# OpenTallas memory compiler (tools/mem_compiler), ASAP7 abstract view
VERSION 5.7 ;
BUSBITCHARS "[]" ;
DIVIDERCHAR "/" ;
PROPERTYDEFINITIONS
  MACRO width INTEGER ;
  MACRO depth INTEGER ;
  MACRO banks INTEGER ;
END PROPERTYDEFINITIONS
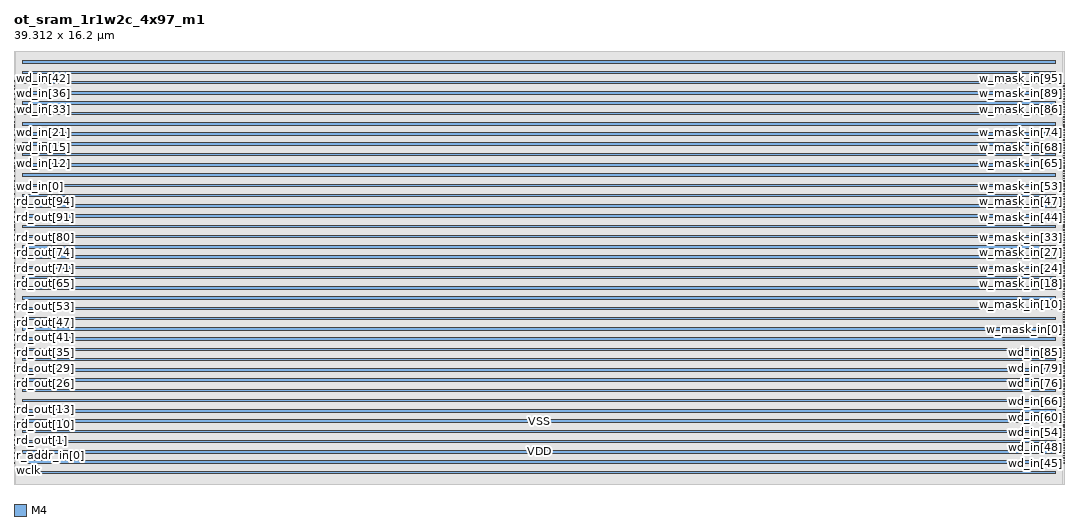
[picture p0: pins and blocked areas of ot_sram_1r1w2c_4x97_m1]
MACRO ot_sram_1r1w2c_4x97_m1
  PROPERTY width 97 ;
  PROPERTY depth 4 ;
  PROPERTY banks 1 ;
  FOREIGN ot_sram_1r1w2c_4x97_m1 0 0 ;
  SYMMETRY X Y R90 ;
  SIZE 39.312 BY 16.200 ;
  CLASS BLOCK ;
  PIN wclk
    DIRECTION INPUT ;
    USE CLOCK ;
    SHAPE ABUTMENT ;
    PORT
      LAYER M4 ;
      RECT 0.000 0.768 0.024 0.792 ;
    END
  END wclk
  PIN rclk
    DIRECTION INPUT ;
    USE CLOCK ;
    SHAPE ABUTMENT ;
    PORT
      LAYER M4 ;
      RECT 0.000 0.864 0.024 0.888 ;
    END
  END rclk
  PIN r_ce_in
    DIRECTION INPUT ;
    USE SIGNAL ;
    SHAPE ABUTMENT ;
    PORT
      LAYER M4 ;
      RECT 0.000 0.960 0.024 0.984 ;
    END
  END r_ce_in
  PIN r_addr_in[0]
    DIRECTION INPUT ;
    USE SIGNAL ;
    SHAPE ABUTMENT ;
    PORT
      LAYER M4 ;
      RECT 0.000 1.056 0.024 1.080 ;
    END
  END r_addr_in[0]
  PIN r_addr_in[1]
    DIRECTION INPUT ;
    USE SIGNAL ;
    SHAPE ABUTMENT ;
    PORT
      LAYER M4 ;
      RECT 0.000 1.152 0.024 1.176 ;
    END
  END r_addr_in[1]
  PIN rd_out[0]
    DIRECTION OUTPUT ;
    USE SIGNAL ;
    SHAPE ABUTMENT ;
    PORT
      LAYER M4 ;
      RECT 0.000 1.248 0.024 1.272 ;
    END
  END rd_out[0]
  PIN rd_out[1]
    DIRECTION OUTPUT ;
    USE SIGNAL ;
    SHAPE ABUTMENT ;
    PORT
      LAYER M4 ;
      RECT 0.000 1.344 0.024 1.368 ;
    END
  END rd_out[1]
  PIN rd_out[2]
    DIRECTION OUTPUT ;
    USE SIGNAL ;
    SHAPE ABUTMENT ;
    PORT
      LAYER M4 ;
      RECT 0.000 1.440 0.024 1.464 ;
    END
  END rd_out[2]
  PIN rd_out[3]
    DIRECTION OUTPUT ;
    USE SIGNAL ;
    SHAPE ABUTMENT ;
    PORT
      LAYER M4 ;
      RECT 0.000 1.536 0.024 1.560 ;
    END
  END rd_out[3]
  PIN rd_out[4]
    DIRECTION OUTPUT ;
    USE SIGNAL ;
    SHAPE ABUTMENT ;
    PORT
      LAYER M4 ;
      RECT 0.000 1.632 0.024 1.656 ;
    END
  END rd_out[4]
  PIN rd_out[5]
    DIRECTION OUTPUT ;
    USE SIGNAL ;
    SHAPE ABUTMENT ;
    PORT
      LAYER M4 ;
      RECT 0.000 1.728 0.024 1.752 ;
    END
  END rd_out[5]
  PIN rd_out[6]
    DIRECTION OUTPUT ;
    USE SIGNAL ;
    SHAPE ABUTMENT ;
    PORT
      LAYER M4 ;
      RECT 0.000 1.824 0.024 1.848 ;
    END
  END rd_out[6]
  PIN rd_out[7]
    DIRECTION OUTPUT ;
    USE SIGNAL ;
    SHAPE ABUTMENT ;
    PORT
      LAYER M4 ;
      RECT 0.000 1.920 0.024 1.944 ;
    END
  END rd_out[7]
  PIN rd_out[8]
    DIRECTION OUTPUT ;
    USE SIGNAL ;
    SHAPE ABUTMENT ;
    PORT
      LAYER M4 ;
      RECT 0.000 2.016 0.024 2.040 ;
    END
  END rd_out[8]
  PIN rd_out[9]
    DIRECTION OUTPUT ;
    USE SIGNAL ;
    SHAPE ABUTMENT ;
    PORT
      LAYER M4 ;
      RECT 0.000 2.112 0.024 2.136 ;
    END
  END rd_out[9]
  PIN rd_out[10]
    DIRECTION OUTPUT ;
    USE SIGNAL ;
    SHAPE ABUTMENT ;
    PORT
      LAYER M4 ;
      RECT 0.000 2.208 0.024 2.232 ;
    END
  END rd_out[10]
  PIN rd_out[11]
    DIRECTION OUTPUT ;
    USE SIGNAL ;
    SHAPE ABUTMENT ;
    PORT
      LAYER M4 ;
      RECT 0.000 2.304 0.024 2.328 ;
    END
  END rd_out[11]
  PIN rd_out[12]
    DIRECTION OUTPUT ;
    USE SIGNAL ;
    SHAPE ABUTMENT ;
    PORT
      LAYER M4 ;
      RECT 0.000 2.400 0.024 2.424 ;
    END
  END rd_out[12]
  PIN rd_out[13]
    DIRECTION OUTPUT ;
    USE SIGNAL ;
    SHAPE ABUTMENT ;
    PORT
      LAYER M4 ;
      RECT 0.000 2.496 0.024 2.520 ;
    END
  END rd_out[13]
  PIN rd_out[14]
    DIRECTION OUTPUT ;
    USE SIGNAL ;
    SHAPE ABUTMENT ;
    PORT
      LAYER M4 ;
      RECT 0.000 2.592 0.024 2.616 ;
    END
  END rd_out[14]
  PIN rd_out[15]
    DIRECTION OUTPUT ;
    USE SIGNAL ;
    SHAPE ABUTMENT ;
    PORT
      LAYER M4 ;
      RECT 0.000 2.688 0.024 2.712 ;
    END
  END rd_out[15]
  PIN rd_out[16]
    DIRECTION OUTPUT ;
    USE SIGNAL ;
    SHAPE ABUTMENT ;
    PORT
      LAYER M4 ;
      RECT 0.000 2.784 0.024 2.808 ;
    END
  END rd_out[16]
  PIN rd_out[17]
    DIRECTION OUTPUT ;
    USE SIGNAL ;
    SHAPE ABUTMENT ;
    PORT
      LAYER M4 ;
      RECT 0.000 2.880 0.024 2.904 ;
    END
  END rd_out[17]
  PIN rd_out[18]
    DIRECTION OUTPUT ;
    USE SIGNAL ;
    SHAPE ABUTMENT ;
    PORT
      LAYER M4 ;
      RECT 0.000 2.976 0.024 3.000 ;
    END
  END rd_out[18]
  PIN rd_out[19]
    DIRECTION OUTPUT ;
    USE SIGNAL ;
    SHAPE ABUTMENT ;
    PORT
      LAYER M4 ;
      RECT 0.000 3.072 0.024 3.096 ;
    END
  END rd_out[19]
  PIN rd_out[20]
    DIRECTION OUTPUT ;
    USE SIGNAL ;
    SHAPE ABUTMENT ;
    PORT
      LAYER M4 ;
      RECT 0.000 3.168 0.024 3.192 ;
    END
  END rd_out[20]
  PIN rd_out[21]
    DIRECTION OUTPUT ;
    USE SIGNAL ;
    SHAPE ABUTMENT ;
    PORT
      LAYER M4 ;
      RECT 0.000 3.264 0.024 3.288 ;
    END
  END rd_out[21]
  PIN rd_out[22]
    DIRECTION OUTPUT ;
    USE SIGNAL ;
    SHAPE ABUTMENT ;
    PORT
      LAYER M4 ;
      RECT 0.000 3.360 0.024 3.384 ;
    END
  END rd_out[22]
  PIN rd_out[23]
    DIRECTION OUTPUT ;
    USE SIGNAL ;
    SHAPE ABUTMENT ;
    PORT
      LAYER M4 ;
      RECT 0.000 3.456 0.024 3.480 ;
    END
  END rd_out[23]
  PIN rd_out[24]
    DIRECTION OUTPUT ;
    USE SIGNAL ;
    SHAPE ABUTMENT ;
    PORT
      LAYER M4 ;
      RECT 0.000 3.552 0.024 3.576 ;
    END
  END rd_out[24]
  PIN rd_out[25]
    DIRECTION OUTPUT ;
    USE SIGNAL ;
    SHAPE ABUTMENT ;
    PORT
      LAYER M4 ;
      RECT 0.000 3.648 0.024 3.672 ;
    END
  END rd_out[25]
  PIN rd_out[26]
    DIRECTION OUTPUT ;
    USE SIGNAL ;
    SHAPE ABUTMENT ;
    PORT
      LAYER M4 ;
      RECT 0.000 3.744 0.024 3.768 ;
    END
  END rd_out[26]
  PIN rd_out[27]
    DIRECTION OUTPUT ;
    USE SIGNAL ;
    SHAPE ABUTMENT ;
    PORT
      LAYER M4 ;
      RECT 0.000 3.840 0.024 3.864 ;
    END
  END rd_out[27]
  PIN rd_out[28]
    DIRECTION OUTPUT ;
    USE SIGNAL ;
    SHAPE ABUTMENT ;
    PORT
      LAYER M4 ;
      RECT 0.000 3.936 0.024 3.960 ;
    END
  END rd_out[28]
  PIN rd_out[29]
    DIRECTION OUTPUT ;
    USE SIGNAL ;
    SHAPE ABUTMENT ;
    PORT
      LAYER M4 ;
      RECT 0.000 4.032 0.024 4.056 ;
    END
  END rd_out[29]
  PIN rd_out[30]
    DIRECTION OUTPUT ;
    USE SIGNAL ;
    SHAPE ABUTMENT ;
    PORT
      LAYER M4 ;
      RECT 0.000 4.128 0.024 4.152 ;
    END
  END rd_out[30]
  PIN rd_out[31]
    DIRECTION OUTPUT ;
    USE SIGNAL ;
    SHAPE ABUTMENT ;
    PORT
      LAYER M4 ;
      RECT 0.000 4.224 0.024 4.248 ;
    END
  END rd_out[31]
  PIN rd_out[32]
    DIRECTION OUTPUT ;
    USE SIGNAL ;
    SHAPE ABUTMENT ;
    PORT
      LAYER M4 ;
      RECT 0.000 4.320 0.024 4.344 ;
    END
  END rd_out[32]
  PIN rd_out[33]
    DIRECTION OUTPUT ;
    USE SIGNAL ;
    SHAPE ABUTMENT ;
    PORT
      LAYER M4 ;
      RECT 0.000 4.416 0.024 4.440 ;
    END
  END rd_out[33]
  PIN rd_out[34]
    DIRECTION OUTPUT ;
    USE SIGNAL ;
    SHAPE ABUTMENT ;
    PORT
      LAYER M4 ;
      RECT 0.000 4.512 0.024 4.536 ;
    END
  END rd_out[34]
  PIN rd_out[35]
    DIRECTION OUTPUT ;
    USE SIGNAL ;
    SHAPE ABUTMENT ;
    PORT
      LAYER M4 ;
      RECT 0.000 4.608 0.024 4.632 ;
    END
  END rd_out[35]
  PIN rd_out[36]
    DIRECTION OUTPUT ;
    USE SIGNAL ;
    SHAPE ABUTMENT ;
    PORT
      LAYER M4 ;
      RECT 0.000 4.704 0.024 4.728 ;
    END
  END rd_out[36]
  PIN rd_out[37]
    DIRECTION OUTPUT ;
    USE SIGNAL ;
    SHAPE ABUTMENT ;
    PORT
      LAYER M4 ;
      RECT 0.000 4.800 0.024 4.824 ;
    END
  END rd_out[37]
  PIN rd_out[38]
    DIRECTION OUTPUT ;
    USE SIGNAL ;
    SHAPE ABUTMENT ;
    PORT
      LAYER M4 ;
      RECT 0.000 4.896 0.024 4.920 ;
    END
  END rd_out[38]
  PIN rd_out[39]
    DIRECTION OUTPUT ;
    USE SIGNAL ;
    SHAPE ABUTMENT ;
    PORT
      LAYER M4 ;
      RECT 0.000 4.992 0.024 5.016 ;
    END
  END rd_out[39]
  PIN rd_out[40]
    DIRECTION OUTPUT ;
    USE SIGNAL ;
    SHAPE ABUTMENT ;
    PORT
      LAYER M4 ;
      RECT 0.000 5.088 0.024 5.112 ;
    END
  END rd_out[40]
  PIN rd_out[41]
    DIRECTION OUTPUT ;
    USE SIGNAL ;
    SHAPE ABUTMENT ;
    PORT
      LAYER M4 ;
      RECT 0.000 5.184 0.024 5.208 ;
    END
  END rd_out[41]
  PIN rd_out[42]
    DIRECTION OUTPUT ;
    USE SIGNAL ;
    SHAPE ABUTMENT ;
    PORT
      LAYER M4 ;
      RECT 0.000 5.280 0.024 5.304 ;
    END
  END rd_out[42]
  PIN rd_out[43]
    DIRECTION OUTPUT ;
    USE SIGNAL ;
    SHAPE ABUTMENT ;
    PORT
      LAYER M4 ;
      RECT 0.000 5.376 0.024 5.400 ;
    END
  END rd_out[43]
  PIN rd_out[44]
    DIRECTION OUTPUT ;
    USE SIGNAL ;
    SHAPE ABUTMENT ;
    PORT
      LAYER M4 ;
      RECT 0.000 5.472 0.024 5.496 ;
    END
  END rd_out[44]
  PIN rd_out[45]
    DIRECTION OUTPUT ;
    USE SIGNAL ;
    SHAPE ABUTMENT ;
    PORT
      LAYER M4 ;
      RECT 0.000 5.568 0.024 5.592 ;
    END
  END rd_out[45]
  PIN rd_out[46]
    DIRECTION OUTPUT ;
    USE SIGNAL ;
    SHAPE ABUTMENT ;
    PORT
      LAYER M4 ;
      RECT 0.000 5.664 0.024 5.688 ;
    END
  END rd_out[46]
  PIN rd_out[47]
    DIRECTION OUTPUT ;
    USE SIGNAL ;
    SHAPE ABUTMENT ;
    PORT
      LAYER M4 ;
      RECT 0.000 5.760 0.024 5.784 ;
    END
  END rd_out[47]
  PIN rd_out[48]
    DIRECTION OUTPUT ;
    USE SIGNAL ;
    SHAPE ABUTMENT ;
    PORT
      LAYER M4 ;
      RECT 0.000 5.856 0.024 5.880 ;
    END
  END rd_out[48]
  PIN rd_out[49]
    DIRECTION OUTPUT ;
    USE SIGNAL ;
    SHAPE ABUTMENT ;
    PORT
      LAYER M4 ;
      RECT 0.000 5.952 0.024 5.976 ;
    END
  END rd_out[49]
  PIN rd_out[50]
    DIRECTION OUTPUT ;
    USE SIGNAL ;
    SHAPE ABUTMENT ;
    PORT
      LAYER M4 ;
      RECT 0.000 6.048 0.024 6.072 ;
    END
  END rd_out[50]
  PIN rd_out[51]
    DIRECTION OUTPUT ;
    USE SIGNAL ;
    SHAPE ABUTMENT ;
    PORT
      LAYER M4 ;
      RECT 0.000 6.144 0.024 6.168 ;
    END
  END rd_out[51]
  PIN rd_out[52]
    DIRECTION OUTPUT ;
    USE SIGNAL ;
    SHAPE ABUTMENT ;
    PORT
      LAYER M4 ;
      RECT 0.000 6.240 0.024 6.264 ;
    END
  END rd_out[52]
  PIN rd_out[53]
    DIRECTION OUTPUT ;
    USE SIGNAL ;
    SHAPE ABUTMENT ;
    PORT
      LAYER M4 ;
      RECT 0.000 6.336 0.024 6.360 ;
    END
  END rd_out[53]
  PIN rd_out[54]
    DIRECTION OUTPUT ;
    USE SIGNAL ;
    SHAPE ABUTMENT ;
    PORT
      LAYER M4 ;
      RECT 0.000 6.432 0.024 6.456 ;
    END
  END rd_out[54]
  PIN rd_out[55]
    DIRECTION OUTPUT ;
    USE SIGNAL ;
    SHAPE ABUTMENT ;
    PORT
      LAYER M4 ;
      RECT 0.000 6.528 0.024 6.552 ;
    END
  END rd_out[55]
  PIN rd_out[56]
    DIRECTION OUTPUT ;
    USE SIGNAL ;
    SHAPE ABUTMENT ;
    PORT
      LAYER M4 ;
      RECT 0.000 6.624 0.024 6.648 ;
    END
  END rd_out[56]
  PIN rd_out[57]
    DIRECTION OUTPUT ;
    USE SIGNAL ;
    SHAPE ABUTMENT ;
    PORT
      LAYER M4 ;
      RECT 0.000 6.720 0.024 6.744 ;
    END
  END rd_out[57]
  PIN rd_out[58]
    DIRECTION OUTPUT ;
    USE SIGNAL ;
    SHAPE ABUTMENT ;
    PORT
      LAYER M4 ;
      RECT 0.000 6.816 0.024 6.840 ;
    END
  END rd_out[58]
  PIN rd_out[59]
    DIRECTION OUTPUT ;
    USE SIGNAL ;
    SHAPE ABUTMENT ;
    PORT
      LAYER M4 ;
      RECT 0.000 6.912 0.024 6.936 ;
    END
  END rd_out[59]
  PIN rd_out[60]
    DIRECTION OUTPUT ;
    USE SIGNAL ;
    SHAPE ABUTMENT ;
    PORT
      LAYER M4 ;
      RECT 0.000 7.008 0.024 7.032 ;
    END
  END rd_out[60]
  PIN rd_out[61]
    DIRECTION OUTPUT ;
    USE SIGNAL ;
    SHAPE ABUTMENT ;
    PORT
      LAYER M4 ;
      RECT 0.000 7.104 0.024 7.128 ;
    END
  END rd_out[61]
  PIN rd_out[62]
    DIRECTION OUTPUT ;
    USE SIGNAL ;
    SHAPE ABUTMENT ;
    PORT
      LAYER M4 ;
      RECT 0.000 7.200 0.024 7.224 ;
    END
  END rd_out[62]
  PIN rd_out[63]
    DIRECTION OUTPUT ;
    USE SIGNAL ;
    SHAPE ABUTMENT ;
    PORT
      LAYER M4 ;
      RECT 0.000 7.296 0.024 7.320 ;
    END
  END rd_out[63]
  PIN rd_out[64]
    DIRECTION OUTPUT ;
    USE SIGNAL ;
    SHAPE ABUTMENT ;
    PORT
      LAYER M4 ;
      RECT 0.000 7.392 0.024 7.416 ;
    END
  END rd_out[64]
  PIN rd_out[65]
    DIRECTION OUTPUT ;
    USE SIGNAL ;
    SHAPE ABUTMENT ;
    PORT
      LAYER M4 ;
      RECT 0.000 7.488 0.024 7.512 ;
    END
  END rd_out[65]
  PIN rd_out[66]
    DIRECTION OUTPUT ;
    USE SIGNAL ;
    SHAPE ABUTMENT ;
    PORT
      LAYER M4 ;
      RECT 0.000 7.584 0.024 7.608 ;
    END
  END rd_out[66]
  PIN rd_out[67]
    DIRECTION OUTPUT ;
    USE SIGNAL ;
    SHAPE ABUTMENT ;
    PORT
      LAYER M4 ;
      RECT 0.000 7.680 0.024 7.704 ;
    END
  END rd_out[67]
  PIN rd_out[68]
    DIRECTION OUTPUT ;
    USE SIGNAL ;
    SHAPE ABUTMENT ;
    PORT
      LAYER M4 ;
      RECT 0.000 7.776 0.024 7.800 ;
    END
  END rd_out[68]
  PIN rd_out[69]
    DIRECTION OUTPUT ;
    USE SIGNAL ;
    SHAPE ABUTMENT ;
    PORT
      LAYER M4 ;
      RECT 0.000 7.872 0.024 7.896 ;
    END
  END rd_out[69]
  PIN rd_out[70]
    DIRECTION OUTPUT ;
    USE SIGNAL ;
    SHAPE ABUTMENT ;
    PORT
      LAYER M4 ;
      RECT 0.000 7.968 0.024 7.992 ;
    END
  END rd_out[70]
  PIN rd_out[71]
    DIRECTION OUTPUT ;
    USE SIGNAL ;
    SHAPE ABUTMENT ;
    PORT
      LAYER M4 ;
      RECT 0.000 8.064 0.024 8.088 ;
    END
  END rd_out[71]
  PIN rd_out[72]
    DIRECTION OUTPUT ;
    USE SIGNAL ;
    SHAPE ABUTMENT ;
    PORT
      LAYER M4 ;
      RECT 0.000 8.160 0.024 8.184 ;
    END
  END rd_out[72]
  PIN rd_out[73]
    DIRECTION OUTPUT ;
    USE SIGNAL ;
    SHAPE ABUTMENT ;
    PORT
      LAYER M4 ;
      RECT 0.000 8.256 0.024 8.280 ;
    END
  END rd_out[73]
  PIN rd_out[74]
    DIRECTION OUTPUT ;
    USE SIGNAL ;
    SHAPE ABUTMENT ;
    PORT
      LAYER M4 ;
      RECT 0.000 8.352 0.024 8.376 ;
    END
  END rd_out[74]
  PIN rd_out[75]
    DIRECTION OUTPUT ;
    USE SIGNAL ;
    SHAPE ABUTMENT ;
    PORT
      LAYER M4 ;
      RECT 0.000 8.448 0.024 8.472 ;
    END
  END rd_out[75]
  PIN rd_out[76]
    DIRECTION OUTPUT ;
    USE SIGNAL ;
    SHAPE ABUTMENT ;
    PORT
      LAYER M4 ;
      RECT 0.000 8.544 0.024 8.568 ;
    END
  END rd_out[76]
  PIN rd_out[77]
    DIRECTION OUTPUT ;
    USE SIGNAL ;
    SHAPE ABUTMENT ;
    PORT
      LAYER M4 ;
      RECT 0.000 8.640 0.024 8.664 ;
    END
  END rd_out[77]
  PIN rd_out[78]
    DIRECTION OUTPUT ;
    USE SIGNAL ;
    SHAPE ABUTMENT ;
    PORT
      LAYER M4 ;
      RECT 0.000 8.736 0.024 8.760 ;
    END
  END rd_out[78]
  PIN rd_out[79]
    DIRECTION OUTPUT ;
    USE SIGNAL ;
    SHAPE ABUTMENT ;
    PORT
      LAYER M4 ;
      RECT 0.000 8.832 0.024 8.856 ;
    END
  END rd_out[79]
  PIN rd_out[80]
    DIRECTION OUTPUT ;
    USE SIGNAL ;
    SHAPE ABUTMENT ;
    PORT
      LAYER M4 ;
      RECT 0.000 8.928 0.024 8.952 ;
    END
  END rd_out[80]
  PIN rd_out[81]
    DIRECTION OUTPUT ;
    USE SIGNAL ;
    SHAPE ABUTMENT ;
    PORT
      LAYER M4 ;
      RECT 0.000 9.024 0.024 9.048 ;
    END
  END rd_out[81]
  PIN rd_out[82]
    DIRECTION OUTPUT ;
    USE SIGNAL ;
    SHAPE ABUTMENT ;
    PORT
      LAYER M4 ;
      RECT 0.000 9.120 0.024 9.144 ;
    END
  END rd_out[82]
  PIN rd_out[83]
    DIRECTION OUTPUT ;
    USE SIGNAL ;
    SHAPE ABUTMENT ;
    PORT
      LAYER M4 ;
      RECT 0.000 9.216 0.024 9.240 ;
    END
  END rd_out[83]
  PIN rd_out[84]
    DIRECTION OUTPUT ;
    USE SIGNAL ;
    SHAPE ABUTMENT ;
    PORT
      LAYER M4 ;
      RECT 0.000 9.312 0.024 9.336 ;
    END
  END rd_out[84]
  PIN rd_out[85]
    DIRECTION OUTPUT ;
    USE SIGNAL ;
    SHAPE ABUTMENT ;
    PORT
      LAYER M4 ;
      RECT 0.000 9.408 0.024 9.432 ;
    END
  END rd_out[85]
  PIN rd_out[86]
    DIRECTION OUTPUT ;
    USE SIGNAL ;
    SHAPE ABUTMENT ;
    PORT
      LAYER M4 ;
      RECT 0.000 9.504 0.024 9.528 ;
    END
  END rd_out[86]
  PIN rd_out[87]
    DIRECTION OUTPUT ;
    USE SIGNAL ;
    SHAPE ABUTMENT ;
    PORT
      LAYER M4 ;
      RECT 0.000 9.600 0.024 9.624 ;
    END
  END rd_out[87]
  PIN rd_out[88]
    DIRECTION OUTPUT ;
    USE SIGNAL ;
    SHAPE ABUTMENT ;
    PORT
      LAYER M4 ;
      RECT 0.000 9.696 0.024 9.720 ;
    END
  END rd_out[88]
  PIN rd_out[89]
    DIRECTION OUTPUT ;
    USE SIGNAL ;
    SHAPE ABUTMENT ;
    PORT
      LAYER M4 ;
      RECT 0.000 9.792 0.024 9.816 ;
    END
  END rd_out[89]
  PIN rd_out[90]
    DIRECTION OUTPUT ;
    USE SIGNAL ;
    SHAPE ABUTMENT ;
    PORT
      LAYER M4 ;
      RECT 0.000 9.888 0.024 9.912 ;
    END
  END rd_out[90]
  PIN rd_out[91]
    DIRECTION OUTPUT ;
    USE SIGNAL ;
    SHAPE ABUTMENT ;
    PORT
      LAYER M4 ;
      RECT 0.000 9.984 0.024 10.008 ;
    END
  END rd_out[91]
  PIN rd_out[92]
    DIRECTION OUTPUT ;
    USE SIGNAL ;
    SHAPE ABUTMENT ;
    PORT
      LAYER M4 ;
      RECT 0.000 10.080 0.024 10.104 ;
    END
  END rd_out[92]
  PIN rd_out[93]
    DIRECTION OUTPUT ;
    USE SIGNAL ;
    SHAPE ABUTMENT ;
    PORT
      LAYER M4 ;
      RECT 0.000 10.176 0.024 10.200 ;
    END
  END rd_out[93]
  PIN rd_out[94]
    DIRECTION OUTPUT ;
    USE SIGNAL ;
    SHAPE ABUTMENT ;
    PORT
      LAYER M4 ;
      RECT 0.000 10.272 0.024 10.296 ;
    END
  END rd_out[94]
  PIN rd_out[95]
    DIRECTION OUTPUT ;
    USE SIGNAL ;
    SHAPE ABUTMENT ;
    PORT
      LAYER M4 ;
      RECT 0.000 10.368 0.024 10.392 ;
    END
  END rd_out[95]
  PIN rd_out[96]
    DIRECTION OUTPUT ;
    USE SIGNAL ;
    SHAPE ABUTMENT ;
    PORT
      LAYER M4 ;
      RECT 0.000 10.464 0.024 10.488 ;
    END
  END rd_out[96]
  PIN w_ce_in
    DIRECTION INPUT ;
    USE SIGNAL ;
    SHAPE ABUTMENT ;
    PORT
      LAYER M4 ;
      RECT 0.000 10.560 0.024 10.584 ;
    END
  END w_ce_in
  PIN w_addr_in[0]
    DIRECTION INPUT ;
    USE SIGNAL ;
    SHAPE ABUTMENT ;
    PORT
      LAYER M4 ;
      RECT 0.000 10.656 0.024 10.680 ;
    END
  END w_addr_in[0]
  PIN w_addr_in[1]
    DIRECTION INPUT ;
    USE SIGNAL ;
    SHAPE ABUTMENT ;
    PORT
      LAYER M4 ;
      RECT 0.000 10.752 0.024 10.776 ;
    END
  END w_addr_in[1]
  PIN wd_in[0]
    DIRECTION INPUT ;
    USE SIGNAL ;
    SHAPE ABUTMENT ;
    PORT
      LAYER M4 ;
      RECT 0.000 10.848 0.024 10.872 ;
    END
  END wd_in[0]
  PIN wd_in[1]
    DIRECTION INPUT ;
    USE SIGNAL ;
    SHAPE ABUTMENT ;
    PORT
      LAYER M4 ;
      RECT 0.000 10.944 0.024 10.968 ;
    END
  END wd_in[1]
  PIN wd_in[2]
    DIRECTION INPUT ;
    USE SIGNAL ;
    SHAPE ABUTMENT ;
    PORT
      LAYER M4 ;
      RECT 0.000 11.040 0.024 11.064 ;
    END
  END wd_in[2]
  PIN wd_in[3]
    DIRECTION INPUT ;
    USE SIGNAL ;
    SHAPE ABUTMENT ;
    PORT
      LAYER M4 ;
      RECT 0.000 11.136 0.024 11.160 ;
    END
  END wd_in[3]
  PIN wd_in[4]
    DIRECTION INPUT ;
    USE SIGNAL ;
    SHAPE ABUTMENT ;
    PORT
      LAYER M4 ;
      RECT 0.000 11.232 0.024 11.256 ;
    END
  END wd_in[4]
  PIN wd_in[5]
    DIRECTION INPUT ;
    USE SIGNAL ;
    SHAPE ABUTMENT ;
    PORT
      LAYER M4 ;
      RECT 0.000 11.328 0.024 11.352 ;
    END
  END wd_in[5]
  PIN wd_in[6]
    DIRECTION INPUT ;
    USE SIGNAL ;
    SHAPE ABUTMENT ;
    PORT
      LAYER M4 ;
      RECT 0.000 11.424 0.024 11.448 ;
    END
  END wd_in[6]
  PIN wd_in[7]
    DIRECTION INPUT ;
    USE SIGNAL ;
    SHAPE ABUTMENT ;
    PORT
      LAYER M4 ;
      RECT 0.000 11.520 0.024 11.544 ;
    END
  END wd_in[7]
  PIN wd_in[8]
    DIRECTION INPUT ;
    USE SIGNAL ;
    SHAPE ABUTMENT ;
    PORT
      LAYER M4 ;
      RECT 0.000 11.616 0.024 11.640 ;
    END
  END wd_in[8]
  PIN wd_in[9]
    DIRECTION INPUT ;
    USE SIGNAL ;
    SHAPE ABUTMENT ;
    PORT
      LAYER M4 ;
      RECT 0.000 11.712 0.024 11.736 ;
    END
  END wd_in[9]
  PIN wd_in[10]
    DIRECTION INPUT ;
    USE SIGNAL ;
    SHAPE ABUTMENT ;
    PORT
      LAYER M4 ;
      RECT 0.000 11.808 0.024 11.832 ;
    END
  END wd_in[10]
  PIN wd_in[11]
    DIRECTION INPUT ;
    USE SIGNAL ;
    SHAPE ABUTMENT ;
    PORT
      LAYER M4 ;
      RECT 0.000 11.904 0.024 11.928 ;
    END
  END wd_in[11]
  PIN wd_in[12]
    DIRECTION INPUT ;
    USE SIGNAL ;
    SHAPE ABUTMENT ;
    PORT
      LAYER M4 ;
      RECT 0.000 12.000 0.024 12.024 ;
    END
  END wd_in[12]
  PIN wd_in[13]
    DIRECTION INPUT ;
    USE SIGNAL ;
    SHAPE ABUTMENT ;
    PORT
      LAYER M4 ;
      RECT 0.000 12.096 0.024 12.120 ;
    END
  END wd_in[13]
  PIN wd_in[14]
    DIRECTION INPUT ;
    USE SIGNAL ;
    SHAPE ABUTMENT ;
    PORT
      LAYER M4 ;
      RECT 0.000 12.192 0.024 12.216 ;
    END
  END wd_in[14]
  PIN wd_in[15]
    DIRECTION INPUT ;
    USE SIGNAL ;
    SHAPE ABUTMENT ;
    PORT
      LAYER M4 ;
      RECT 0.000 12.288 0.024 12.312 ;
    END
  END wd_in[15]
  PIN wd_in[16]
    DIRECTION INPUT ;
    USE SIGNAL ;
    SHAPE ABUTMENT ;
    PORT
      LAYER M4 ;
      RECT 0.000 12.384 0.024 12.408 ;
    END
  END wd_in[16]
  PIN wd_in[17]
    DIRECTION INPUT ;
    USE SIGNAL ;
    SHAPE ABUTMENT ;
    PORT
      LAYER M4 ;
      RECT 0.000 12.480 0.024 12.504 ;
    END
  END wd_in[17]
  PIN wd_in[18]
    DIRECTION INPUT ;
    USE SIGNAL ;
    SHAPE ABUTMENT ;
    PORT
      LAYER M4 ;
      RECT 0.000 12.576 0.024 12.600 ;
    END
  END wd_in[18]
  PIN wd_in[19]
    DIRECTION INPUT ;
    USE SIGNAL ;
    SHAPE ABUTMENT ;
    PORT
      LAYER M4 ;
      RECT 0.000 12.672 0.024 12.696 ;
    END
  END wd_in[19]
  PIN wd_in[20]
    DIRECTION INPUT ;
    USE SIGNAL ;
    SHAPE ABUTMENT ;
    PORT
      LAYER M4 ;
      RECT 0.000 12.768 0.024 12.792 ;
    END
  END wd_in[20]
  PIN wd_in[21]
    DIRECTION INPUT ;
    USE SIGNAL ;
    SHAPE ABUTMENT ;
    PORT
      LAYER M4 ;
      RECT 0.000 12.864 0.024 12.888 ;
    END
  END wd_in[21]
  PIN wd_in[22]
    DIRECTION INPUT ;
    USE SIGNAL ;
    SHAPE ABUTMENT ;
    PORT
      LAYER M4 ;
      RECT 0.000 12.960 0.024 12.984 ;
    END
  END wd_in[22]
  PIN wd_in[23]
    DIRECTION INPUT ;
    USE SIGNAL ;
    SHAPE ABUTMENT ;
    PORT
      LAYER M4 ;
      RECT 0.000 13.056 0.024 13.080 ;
    END
  END wd_in[23]
  PIN wd_in[24]
    DIRECTION INPUT ;
    USE SIGNAL ;
    SHAPE ABUTMENT ;
    PORT
      LAYER M4 ;
      RECT 0.000 13.152 0.024 13.176 ;
    END
  END wd_in[24]
  PIN wd_in[25]
    DIRECTION INPUT ;
    USE SIGNAL ;
    SHAPE ABUTMENT ;
    PORT
      LAYER M4 ;
      RECT 0.000 13.248 0.024 13.272 ;
    END
  END wd_in[25]
  PIN wd_in[26]
    DIRECTION INPUT ;
    USE SIGNAL ;
    SHAPE ABUTMENT ;
    PORT
      LAYER M4 ;
      RECT 0.000 13.344 0.024 13.368 ;
    END
  END wd_in[26]
  PIN wd_in[27]
    DIRECTION INPUT ;
    USE SIGNAL ;
    SHAPE ABUTMENT ;
    PORT
      LAYER M4 ;
      RECT 0.000 13.440 0.024 13.464 ;
    END
  END wd_in[27]
  PIN wd_in[28]
    DIRECTION INPUT ;
    USE SIGNAL ;
    SHAPE ABUTMENT ;
    PORT
      LAYER M4 ;
      RECT 0.000 13.536 0.024 13.560 ;
    END
  END wd_in[28]
  PIN wd_in[29]
    DIRECTION INPUT ;
    USE SIGNAL ;
    SHAPE ABUTMENT ;
    PORT
      LAYER M4 ;
      RECT 0.000 13.632 0.024 13.656 ;
    END
  END wd_in[29]
  PIN wd_in[30]
    DIRECTION INPUT ;
    USE SIGNAL ;
    SHAPE ABUTMENT ;
    PORT
      LAYER M4 ;
      RECT 0.000 13.728 0.024 13.752 ;
    END
  END wd_in[30]
  PIN wd_in[31]
    DIRECTION INPUT ;
    USE SIGNAL ;
    SHAPE ABUTMENT ;
    PORT
      LAYER M4 ;
      RECT 0.000 13.824 0.024 13.848 ;
    END
  END wd_in[31]
  PIN wd_in[32]
    DIRECTION INPUT ;
    USE SIGNAL ;
    SHAPE ABUTMENT ;
    PORT
      LAYER M4 ;
      RECT 0.000 13.920 0.024 13.944 ;
    END
  END wd_in[32]
  PIN wd_in[33]
    DIRECTION INPUT ;
    USE SIGNAL ;
    SHAPE ABUTMENT ;
    PORT
      LAYER M4 ;
      RECT 0.000 14.016 0.024 14.040 ;
    END
  END wd_in[33]
  PIN wd_in[34]
    DIRECTION INPUT ;
    USE SIGNAL ;
    SHAPE ABUTMENT ;
    PORT
      LAYER M4 ;
      RECT 0.000 14.112 0.024 14.136 ;
    END
  END wd_in[34]
  PIN wd_in[35]
    DIRECTION INPUT ;
    USE SIGNAL ;
    SHAPE ABUTMENT ;
    PORT
      LAYER M4 ;
      RECT 0.000 14.208 0.024 14.232 ;
    END
  END wd_in[35]
  PIN wd_in[36]
    DIRECTION INPUT ;
    USE SIGNAL ;
    SHAPE ABUTMENT ;
    PORT
      LAYER M4 ;
      RECT 0.000 14.304 0.024 14.328 ;
    END
  END wd_in[36]
  PIN wd_in[37]
    DIRECTION INPUT ;
    USE SIGNAL ;
    SHAPE ABUTMENT ;
    PORT
      LAYER M4 ;
      RECT 0.000 14.400 0.024 14.424 ;
    END
  END wd_in[37]
  PIN wd_in[38]
    DIRECTION INPUT ;
    USE SIGNAL ;
    SHAPE ABUTMENT ;
    PORT
      LAYER M4 ;
      RECT 0.000 14.496 0.024 14.520 ;
    END
  END wd_in[38]
  PIN wd_in[39]
    DIRECTION INPUT ;
    USE SIGNAL ;
    SHAPE ABUTMENT ;
    PORT
      LAYER M4 ;
      RECT 0.000 14.592 0.024 14.616 ;
    END
  END wd_in[39]
  PIN wd_in[40]
    DIRECTION INPUT ;
    USE SIGNAL ;
    SHAPE ABUTMENT ;
    PORT
      LAYER M4 ;
      RECT 0.000 14.688 0.024 14.712 ;
    END
  END wd_in[40]
  PIN wd_in[41]
    DIRECTION INPUT ;
    USE SIGNAL ;
    SHAPE ABUTMENT ;
    PORT
      LAYER M4 ;
      RECT 0.000 14.784 0.024 14.808 ;
    END
  END wd_in[41]
  PIN wd_in[42]
    DIRECTION INPUT ;
    USE SIGNAL ;
    SHAPE ABUTMENT ;
    PORT
      LAYER M4 ;
      RECT 0.000 14.880 0.024 14.904 ;
    END
  END wd_in[42]
  PIN wd_in[43]
    DIRECTION INPUT ;
    USE SIGNAL ;
    SHAPE ABUTMENT ;
    PORT
      LAYER M4 ;
      RECT 0.000 14.976 0.024 15.000 ;
    END
  END wd_in[43]
  PIN wd_in[44]
    DIRECTION INPUT ;
    USE SIGNAL ;
    SHAPE ABUTMENT ;
    PORT
      LAYER M4 ;
      RECT 0.000 15.072 0.024 15.096 ;
    END
  END wd_in[44]
  PIN wd_in[45]
    DIRECTION INPUT ;
    USE SIGNAL ;
    SHAPE ABUTMENT ;
    PORT
      LAYER M4 ;
      RECT 39.288 0.768 39.312 0.792 ;
    END
  END wd_in[45]
  PIN wd_in[46]
    DIRECTION INPUT ;
    USE SIGNAL ;
    SHAPE ABUTMENT ;
    PORT
      LAYER M4 ;
      RECT 39.288 0.864 39.312 0.888 ;
    END
  END wd_in[46]
  PIN wd_in[47]
    DIRECTION INPUT ;
    USE SIGNAL ;
    SHAPE ABUTMENT ;
    PORT
      LAYER M4 ;
      RECT 39.288 0.960 39.312 0.984 ;
    END
  END wd_in[47]
  PIN wd_in[48]
    DIRECTION INPUT ;
    USE SIGNAL ;
    SHAPE ABUTMENT ;
    PORT
      LAYER M4 ;
      RECT 39.288 1.056 39.312 1.080 ;
    END
  END wd_in[48]
  PIN wd_in[49]
    DIRECTION INPUT ;
    USE SIGNAL ;
    SHAPE ABUTMENT ;
    PORT
      LAYER M4 ;
      RECT 39.288 1.152 39.312 1.176 ;
    END
  END wd_in[49]
  PIN wd_in[50]
    DIRECTION INPUT ;
    USE SIGNAL ;
    SHAPE ABUTMENT ;
    PORT
      LAYER M4 ;
      RECT 39.288 1.248 39.312 1.272 ;
    END
  END wd_in[50]
  PIN wd_in[51]
    DIRECTION INPUT ;
    USE SIGNAL ;
    SHAPE ABUTMENT ;
    PORT
      LAYER M4 ;
      RECT 39.288 1.344 39.312 1.368 ;
    END
  END wd_in[51]
  PIN wd_in[52]
    DIRECTION INPUT ;
    USE SIGNAL ;
    SHAPE ABUTMENT ;
    PORT
      LAYER M4 ;
      RECT 39.288 1.440 39.312 1.464 ;
    END
  END wd_in[52]
  PIN wd_in[53]
    DIRECTION INPUT ;
    USE SIGNAL ;
    SHAPE ABUTMENT ;
    PORT
      LAYER M4 ;
      RECT 39.288 1.536 39.312 1.560 ;
    END
  END wd_in[53]
  PIN wd_in[54]
    DIRECTION INPUT ;
    USE SIGNAL ;
    SHAPE ABUTMENT ;
    PORT
      LAYER M4 ;
      RECT 39.288 1.632 39.312 1.656 ;
    END
  END wd_in[54]
  PIN wd_in[55]
    DIRECTION INPUT ;
    USE SIGNAL ;
    SHAPE ABUTMENT ;
    PORT
      LAYER M4 ;
      RECT 39.288 1.728 39.312 1.752 ;
    END
  END wd_in[55]
  PIN wd_in[56]
    DIRECTION INPUT ;
    USE SIGNAL ;
    SHAPE ABUTMENT ;
    PORT
      LAYER M4 ;
      RECT 39.288 1.824 39.312 1.848 ;
    END
  END wd_in[56]
  PIN wd_in[57]
    DIRECTION INPUT ;
    USE SIGNAL ;
    SHAPE ABUTMENT ;
    PORT
      LAYER M4 ;
      RECT 39.288 1.920 39.312 1.944 ;
    END
  END wd_in[57]
  PIN wd_in[58]
    DIRECTION INPUT ;
    USE SIGNAL ;
    SHAPE ABUTMENT ;
    PORT
      LAYER M4 ;
      RECT 39.288 2.016 39.312 2.040 ;
    END
  END wd_in[58]
  PIN wd_in[59]
    DIRECTION INPUT ;
    USE SIGNAL ;
    SHAPE ABUTMENT ;
    PORT
      LAYER M4 ;
      RECT 39.288 2.112 39.312 2.136 ;
    END
  END wd_in[59]
  PIN wd_in[60]
    DIRECTION INPUT ;
    USE SIGNAL ;
    SHAPE ABUTMENT ;
    PORT
      LAYER M4 ;
      RECT 39.288 2.208 39.312 2.232 ;
    END
  END wd_in[60]
  PIN wd_in[61]
    DIRECTION INPUT ;
    USE SIGNAL ;
    SHAPE ABUTMENT ;
    PORT
      LAYER M4 ;
      RECT 39.288 2.304 39.312 2.328 ;
    END
  END wd_in[61]
  PIN wd_in[62]
    DIRECTION INPUT ;
    USE SIGNAL ;
    SHAPE ABUTMENT ;
    PORT
      LAYER M4 ;
      RECT 39.288 2.400 39.312 2.424 ;
    END
  END wd_in[62]
  PIN wd_in[63]
    DIRECTION INPUT ;
    USE SIGNAL ;
    SHAPE ABUTMENT ;
    PORT
      LAYER M4 ;
      RECT 39.288 2.496 39.312 2.520 ;
    END
  END wd_in[63]
  PIN wd_in[64]
    DIRECTION INPUT ;
    USE SIGNAL ;
    SHAPE ABUTMENT ;
    PORT
      LAYER M4 ;
      RECT 39.288 2.592 39.312 2.616 ;
    END
  END wd_in[64]
  PIN wd_in[65]
    DIRECTION INPUT ;
    USE SIGNAL ;
    SHAPE ABUTMENT ;
    PORT
      LAYER M4 ;
      RECT 39.288 2.688 39.312 2.712 ;
    END
  END wd_in[65]
  PIN wd_in[66]
    DIRECTION INPUT ;
    USE SIGNAL ;
    SHAPE ABUTMENT ;
    PORT
      LAYER M4 ;
      RECT 39.288 2.784 39.312 2.808 ;
    END
  END wd_in[66]
  PIN wd_in[67]
    DIRECTION INPUT ;
    USE SIGNAL ;
    SHAPE ABUTMENT ;
    PORT
      LAYER M4 ;
      RECT 39.288 2.880 39.312 2.904 ;
    END
  END wd_in[67]
  PIN wd_in[68]
    DIRECTION INPUT ;
    USE SIGNAL ;
    SHAPE ABUTMENT ;
    PORT
      LAYER M4 ;
      RECT 39.288 2.976 39.312 3.000 ;
    END
  END wd_in[68]
  PIN wd_in[69]
    DIRECTION INPUT ;
    USE SIGNAL ;
    SHAPE ABUTMENT ;
    PORT
      LAYER M4 ;
      RECT 39.288 3.072 39.312 3.096 ;
    END
  END wd_in[69]
  PIN wd_in[70]
    DIRECTION INPUT ;
    USE SIGNAL ;
    SHAPE ABUTMENT ;
    PORT
      LAYER M4 ;
      RECT 39.288 3.168 39.312 3.192 ;
    END
  END wd_in[70]
  PIN wd_in[71]
    DIRECTION INPUT ;
    USE SIGNAL ;
    SHAPE ABUTMENT ;
    PORT
      LAYER M4 ;
      RECT 39.288 3.264 39.312 3.288 ;
    END
  END wd_in[71]
  PIN wd_in[72]
    DIRECTION INPUT ;
    USE SIGNAL ;
    SHAPE ABUTMENT ;
    PORT
      LAYER M4 ;
      RECT 39.288 3.360 39.312 3.384 ;
    END
  END wd_in[72]
  PIN wd_in[73]
    DIRECTION INPUT ;
    USE SIGNAL ;
    SHAPE ABUTMENT ;
    PORT
      LAYER M4 ;
      RECT 39.288 3.456 39.312 3.480 ;
    END
  END wd_in[73]
  PIN wd_in[74]
    DIRECTION INPUT ;
    USE SIGNAL ;
    SHAPE ABUTMENT ;
    PORT
      LAYER M4 ;
      RECT 39.288 3.552 39.312 3.576 ;
    END
  END wd_in[74]
  PIN wd_in[75]
    DIRECTION INPUT ;
    USE SIGNAL ;
    SHAPE ABUTMENT ;
    PORT
      LAYER M4 ;
      RECT 39.288 3.648 39.312 3.672 ;
    END
  END wd_in[75]
  PIN wd_in[76]
    DIRECTION INPUT ;
    USE SIGNAL ;
    SHAPE ABUTMENT ;
    PORT
      LAYER M4 ;
      RECT 39.288 3.744 39.312 3.768 ;
    END
  END wd_in[76]
  PIN wd_in[77]
    DIRECTION INPUT ;
    USE SIGNAL ;
    SHAPE ABUTMENT ;
    PORT
      LAYER M4 ;
      RECT 39.288 3.840 39.312 3.864 ;
    END
  END wd_in[77]
  PIN wd_in[78]
    DIRECTION INPUT ;
    USE SIGNAL ;
    SHAPE ABUTMENT ;
    PORT
      LAYER M4 ;
      RECT 39.288 3.936 39.312 3.960 ;
    END
  END wd_in[78]
  PIN wd_in[79]
    DIRECTION INPUT ;
    USE SIGNAL ;
    SHAPE ABUTMENT ;
    PORT
      LAYER M4 ;
      RECT 39.288 4.032 39.312 4.056 ;
    END
  END wd_in[79]
  PIN wd_in[80]
    DIRECTION INPUT ;
    USE SIGNAL ;
    SHAPE ABUTMENT ;
    PORT
      LAYER M4 ;
      RECT 39.288 4.128 39.312 4.152 ;
    END
  END wd_in[80]
  PIN wd_in[81]
    DIRECTION INPUT ;
    USE SIGNAL ;
    SHAPE ABUTMENT ;
    PORT
      LAYER M4 ;
      RECT 39.288 4.224 39.312 4.248 ;
    END
  END wd_in[81]
  PIN wd_in[82]
    DIRECTION INPUT ;
    USE SIGNAL ;
    SHAPE ABUTMENT ;
    PORT
      LAYER M4 ;
      RECT 39.288 4.320 39.312 4.344 ;
    END
  END wd_in[82]
  PIN wd_in[83]
    DIRECTION INPUT ;
    USE SIGNAL ;
    SHAPE ABUTMENT ;
    PORT
      LAYER M4 ;
      RECT 39.288 4.416 39.312 4.440 ;
    END
  END wd_in[83]
  PIN wd_in[84]
    DIRECTION INPUT ;
    USE SIGNAL ;
    SHAPE ABUTMENT ;
    PORT
      LAYER M4 ;
      RECT 39.288 4.512 39.312 4.536 ;
    END
  END wd_in[84]
  PIN wd_in[85]
    DIRECTION INPUT ;
    USE SIGNAL ;
    SHAPE ABUTMENT ;
    PORT
      LAYER M4 ;
      RECT 39.288 4.608 39.312 4.632 ;
    END
  END wd_in[85]
  PIN wd_in[86]
    DIRECTION INPUT ;
    USE SIGNAL ;
    SHAPE ABUTMENT ;
    PORT
      LAYER M4 ;
      RECT 39.288 4.704 39.312 4.728 ;
    END
  END wd_in[86]
  PIN wd_in[87]
    DIRECTION INPUT ;
    USE SIGNAL ;
    SHAPE ABUTMENT ;
    PORT
      LAYER M4 ;
      RECT 39.288 4.800 39.312 4.824 ;
    END
  END wd_in[87]
  PIN wd_in[88]
    DIRECTION INPUT ;
    USE SIGNAL ;
    SHAPE ABUTMENT ;
    PORT
      LAYER M4 ;
      RECT 39.288 4.896 39.312 4.920 ;
    END
  END wd_in[88]
  PIN wd_in[89]
    DIRECTION INPUT ;
    USE SIGNAL ;
    SHAPE ABUTMENT ;
    PORT
      LAYER M4 ;
      RECT 39.288 4.992 39.312 5.016 ;
    END
  END wd_in[89]
  PIN wd_in[90]
    DIRECTION INPUT ;
    USE SIGNAL ;
    SHAPE ABUTMENT ;
    PORT
      LAYER M4 ;
      RECT 39.288 5.088 39.312 5.112 ;
    END
  END wd_in[90]
  PIN wd_in[91]
    DIRECTION INPUT ;
    USE SIGNAL ;
    SHAPE ABUTMENT ;
    PORT
      LAYER M4 ;
      RECT 39.288 5.184 39.312 5.208 ;
    END
  END wd_in[91]
  PIN wd_in[92]
    DIRECTION INPUT ;
    USE SIGNAL ;
    SHAPE ABUTMENT ;
    PORT
      LAYER M4 ;
      RECT 39.288 5.280 39.312 5.304 ;
    END
  END wd_in[92]
  PIN wd_in[93]
    DIRECTION INPUT ;
    USE SIGNAL ;
    SHAPE ABUTMENT ;
    PORT
      LAYER M4 ;
      RECT 39.288 5.376 39.312 5.400 ;
    END
  END wd_in[93]
  PIN wd_in[94]
    DIRECTION INPUT ;
    USE SIGNAL ;
    SHAPE ABUTMENT ;
    PORT
      LAYER M4 ;
      RECT 39.288 5.472 39.312 5.496 ;
    END
  END wd_in[94]
  PIN wd_in[95]
    DIRECTION INPUT ;
    USE SIGNAL ;
    SHAPE ABUTMENT ;
    PORT
      LAYER M4 ;
      RECT 39.288 5.568 39.312 5.592 ;
    END
  END wd_in[95]
  PIN wd_in[96]
    DIRECTION INPUT ;
    USE SIGNAL ;
    SHAPE ABUTMENT ;
    PORT
      LAYER M4 ;
      RECT 39.288 5.664 39.312 5.688 ;
    END
  END wd_in[96]
  PIN w_mask_in[0]
    DIRECTION INPUT ;
    USE SIGNAL ;
    SHAPE ABUTMENT ;
    PORT
      LAYER M4 ;
      RECT 39.288 5.760 39.312 5.784 ;
    END
  END w_mask_in[0]
  PIN w_mask_in[1]
    DIRECTION INPUT ;
    USE SIGNAL ;
    SHAPE ABUTMENT ;
    PORT
      LAYER M4 ;
      RECT 39.288 5.856 39.312 5.880 ;
    END
  END w_mask_in[1]
  PIN w_mask_in[2]
    DIRECTION INPUT ;
    USE SIGNAL ;
    SHAPE ABUTMENT ;
    PORT
      LAYER M4 ;
      RECT 39.288 5.952 39.312 5.976 ;
    END
  END w_mask_in[2]
  PIN w_mask_in[3]
    DIRECTION INPUT ;
    USE SIGNAL ;
    SHAPE ABUTMENT ;
    PORT
      LAYER M4 ;
      RECT 39.288 6.048 39.312 6.072 ;
    END
  END w_mask_in[3]
  PIN w_mask_in[4]
    DIRECTION INPUT ;
    USE SIGNAL ;
    SHAPE ABUTMENT ;
    PORT
      LAYER M4 ;
      RECT 39.288 6.144 39.312 6.168 ;
    END
  END w_mask_in[4]
  PIN w_mask_in[5]
    DIRECTION INPUT ;
    USE SIGNAL ;
    SHAPE ABUTMENT ;
    PORT
      LAYER M4 ;
      RECT 39.288 6.240 39.312 6.264 ;
    END
  END w_mask_in[5]
  PIN w_mask_in[6]
    DIRECTION INPUT ;
    USE SIGNAL ;
    SHAPE ABUTMENT ;
    PORT
      LAYER M4 ;
      RECT 39.288 6.336 39.312 6.360 ;
    END
  END w_mask_in[6]
  PIN w_mask_in[7]
    DIRECTION INPUT ;
    USE SIGNAL ;
    SHAPE ABUTMENT ;
    PORT
      LAYER M4 ;
      RECT 39.288 6.432 39.312 6.456 ;
    END
  END w_mask_in[7]
  PIN w_mask_in[8]
    DIRECTION INPUT ;
    USE SIGNAL ;
    SHAPE ABUTMENT ;
    PORT
      LAYER M4 ;
      RECT 39.288 6.528 39.312 6.552 ;
    END
  END w_mask_in[8]
  PIN w_mask_in[9]
    DIRECTION INPUT ;
    USE SIGNAL ;
    SHAPE ABUTMENT ;
    PORT
      LAYER M4 ;
      RECT 39.288 6.624 39.312 6.648 ;
    END
  END w_mask_in[9]
  PIN w_mask_in[10]
    DIRECTION INPUT ;
    USE SIGNAL ;
    SHAPE ABUTMENT ;
    PORT
      LAYER M4 ;
      RECT 39.288 6.720 39.312 6.744 ;
    END
  END w_mask_in[10]
  PIN w_mask_in[11]
    DIRECTION INPUT ;
    USE SIGNAL ;
    SHAPE ABUTMENT ;
    PORT
      LAYER M4 ;
      RECT 39.288 6.816 39.312 6.840 ;
    END
  END w_mask_in[11]
  PIN w_mask_in[12]
    DIRECTION INPUT ;
    USE SIGNAL ;
    SHAPE ABUTMENT ;
    PORT
      LAYER M4 ;
      RECT 39.288 6.912 39.312 6.936 ;
    END
  END w_mask_in[12]
  PIN w_mask_in[13]
    DIRECTION INPUT ;
    USE SIGNAL ;
    SHAPE ABUTMENT ;
    PORT
      LAYER M4 ;
      RECT 39.288 7.008 39.312 7.032 ;
    END
  END w_mask_in[13]
  PIN w_mask_in[14]
    DIRECTION INPUT ;
    USE SIGNAL ;
    SHAPE ABUTMENT ;
    PORT
      LAYER M4 ;
      RECT 39.288 7.104 39.312 7.128 ;
    END
  END w_mask_in[14]
  PIN w_mask_in[15]
    DIRECTION INPUT ;
    USE SIGNAL ;
    SHAPE ABUTMENT ;
    PORT
      LAYER M4 ;
      RECT 39.288 7.200 39.312 7.224 ;
    END
  END w_mask_in[15]
  PIN w_mask_in[16]
    DIRECTION INPUT ;
    USE SIGNAL ;
    SHAPE ABUTMENT ;
    PORT
      LAYER M4 ;
      RECT 39.288 7.296 39.312 7.320 ;
    END
  END w_mask_in[16]
  PIN w_mask_in[17]
    DIRECTION INPUT ;
    USE SIGNAL ;
    SHAPE ABUTMENT ;
    PORT
      LAYER M4 ;
      RECT 39.288 7.392 39.312 7.416 ;
    END
  END w_mask_in[17]
  PIN w_mask_in[18]
    DIRECTION INPUT ;
    USE SIGNAL ;
    SHAPE ABUTMENT ;
    PORT
      LAYER M4 ;
      RECT 39.288 7.488 39.312 7.512 ;
    END
  END w_mask_in[18]
  PIN w_mask_in[19]
    DIRECTION INPUT ;
    USE SIGNAL ;
    SHAPE ABUTMENT ;
    PORT
      LAYER M4 ;
      RECT 39.288 7.584 39.312 7.608 ;
    END
  END w_mask_in[19]
  PIN w_mask_in[20]
    DIRECTION INPUT ;
    USE SIGNAL ;
    SHAPE ABUTMENT ;
    PORT
      LAYER M4 ;
      RECT 39.288 7.680 39.312 7.704 ;
    END
  END w_mask_in[20]
  PIN w_mask_in[21]
    DIRECTION INPUT ;
    USE SIGNAL ;
    SHAPE ABUTMENT ;
    PORT
      LAYER M4 ;
      RECT 39.288 7.776 39.312 7.800 ;
    END
  END w_mask_in[21]
  PIN w_mask_in[22]
    DIRECTION INPUT ;
    USE SIGNAL ;
    SHAPE ABUTMENT ;
    PORT
      LAYER M4 ;
      RECT 39.288 7.872 39.312 7.896 ;
    END
  END w_mask_in[22]
  PIN w_mask_in[23]
    DIRECTION INPUT ;
    USE SIGNAL ;
    SHAPE ABUTMENT ;
    PORT
      LAYER M4 ;
      RECT 39.288 7.968 39.312 7.992 ;
    END
  END w_mask_in[23]
  PIN w_mask_in[24]
    DIRECTION INPUT ;
    USE SIGNAL ;
    SHAPE ABUTMENT ;
    PORT
      LAYER M4 ;
      RECT 39.288 8.064 39.312 8.088 ;
    END
  END w_mask_in[24]
  PIN w_mask_in[25]
    DIRECTION INPUT ;
    USE SIGNAL ;
    SHAPE ABUTMENT ;
    PORT
      LAYER M4 ;
      RECT 39.288 8.160 39.312 8.184 ;
    END
  END w_mask_in[25]
  PIN w_mask_in[26]
    DIRECTION INPUT ;
    USE SIGNAL ;
    SHAPE ABUTMENT ;
    PORT
      LAYER M4 ;
      RECT 39.288 8.256 39.312 8.280 ;
    END
  END w_mask_in[26]
  PIN w_mask_in[27]
    DIRECTION INPUT ;
    USE SIGNAL ;
    SHAPE ABUTMENT ;
    PORT
      LAYER M4 ;
      RECT 39.288 8.352 39.312 8.376 ;
    END
  END w_mask_in[27]
  PIN w_mask_in[28]
    DIRECTION INPUT ;
    USE SIGNAL ;
    SHAPE ABUTMENT ;
    PORT
      LAYER M4 ;
      RECT 39.288 8.448 39.312 8.472 ;
    END
  END w_mask_in[28]
  PIN w_mask_in[29]
    DIRECTION INPUT ;
    USE SIGNAL ;
    SHAPE ABUTMENT ;
    PORT
      LAYER M4 ;
      RECT 39.288 8.544 39.312 8.568 ;
    END
  END w_mask_in[29]
  PIN w_mask_in[30]
    DIRECTION INPUT ;
    USE SIGNAL ;
    SHAPE ABUTMENT ;
    PORT
      LAYER M4 ;
      RECT 39.288 8.640 39.312 8.664 ;
    END
  END w_mask_in[30]
  PIN w_mask_in[31]
    DIRECTION INPUT ;
    USE SIGNAL ;
    SHAPE ABUTMENT ;
    PORT
      LAYER M4 ;
      RECT 39.288 8.736 39.312 8.760 ;
    END
  END w_mask_in[31]
  PIN w_mask_in[32]
    DIRECTION INPUT ;
    USE SIGNAL ;
    SHAPE ABUTMENT ;
    PORT
      LAYER M4 ;
      RECT 39.288 8.832 39.312 8.856 ;
    END
  END w_mask_in[32]
  PIN w_mask_in[33]
    DIRECTION INPUT ;
    USE SIGNAL ;
    SHAPE ABUTMENT ;
    PORT
      LAYER M4 ;
      RECT 39.288 8.928 39.312 8.952 ;
    END
  END w_mask_in[33]
  PIN w_mask_in[34]
    DIRECTION INPUT ;
    USE SIGNAL ;
    SHAPE ABUTMENT ;
    PORT
      LAYER M4 ;
      RECT 39.288 9.024 39.312 9.048 ;
    END
  END w_mask_in[34]
  PIN w_mask_in[35]
    DIRECTION INPUT ;
    USE SIGNAL ;
    SHAPE ABUTMENT ;
    PORT
      LAYER M4 ;
      RECT 39.288 9.120 39.312 9.144 ;
    END
  END w_mask_in[35]
  PIN w_mask_in[36]
    DIRECTION INPUT ;
    USE SIGNAL ;
    SHAPE ABUTMENT ;
    PORT
      LAYER M4 ;
      RECT 39.288 9.216 39.312 9.240 ;
    END
  END w_mask_in[36]
  PIN w_mask_in[37]
    DIRECTION INPUT ;
    USE SIGNAL ;
    SHAPE ABUTMENT ;
    PORT
      LAYER M4 ;
      RECT 39.288 9.312 39.312 9.336 ;
    END
  END w_mask_in[37]
  PIN w_mask_in[38]
    DIRECTION INPUT ;
    USE SIGNAL ;
    SHAPE ABUTMENT ;
    PORT
      LAYER M4 ;
      RECT 39.288 9.408 39.312 9.432 ;
    END
  END w_mask_in[38]
  PIN w_mask_in[39]
    DIRECTION INPUT ;
    USE SIGNAL ;
    SHAPE ABUTMENT ;
    PORT
      LAYER M4 ;
      RECT 39.288 9.504 39.312 9.528 ;
    END
  END w_mask_in[39]
  PIN w_mask_in[40]
    DIRECTION INPUT ;
    USE SIGNAL ;
    SHAPE ABUTMENT ;
    PORT
      LAYER M4 ;
      RECT 39.288 9.600 39.312 9.624 ;
    END
  END w_mask_in[40]
  PIN w_mask_in[41]
    DIRECTION INPUT ;
    USE SIGNAL ;
    SHAPE ABUTMENT ;
    PORT
      LAYER M4 ;
      RECT 39.288 9.696 39.312 9.720 ;
    END
  END w_mask_in[41]
  PIN w_mask_in[42]
    DIRECTION INPUT ;
    USE SIGNAL ;
    SHAPE ABUTMENT ;
    PORT
      LAYER M4 ;
      RECT 39.288 9.792 39.312 9.816 ;
    END
  END w_mask_in[42]
  PIN w_mask_in[43]
    DIRECTION INPUT ;
    USE SIGNAL ;
    SHAPE ABUTMENT ;
    PORT
      LAYER M4 ;
      RECT 39.288 9.888 39.312 9.912 ;
    END
  END w_mask_in[43]
  PIN w_mask_in[44]
    DIRECTION INPUT ;
    USE SIGNAL ;
    SHAPE ABUTMENT ;
    PORT
      LAYER M4 ;
      RECT 39.288 9.984 39.312 10.008 ;
    END
  END w_mask_in[44]
  PIN w_mask_in[45]
    DIRECTION INPUT ;
    USE SIGNAL ;
    SHAPE ABUTMENT ;
    PORT
      LAYER M4 ;
      RECT 39.288 10.080 39.312 10.104 ;
    END
  END w_mask_in[45]
  PIN w_mask_in[46]
    DIRECTION INPUT ;
    USE SIGNAL ;
    SHAPE ABUTMENT ;
    PORT
      LAYER M4 ;
      RECT 39.288 10.176 39.312 10.200 ;
    END
  END w_mask_in[46]
  PIN w_mask_in[47]
    DIRECTION INPUT ;
    USE SIGNAL ;
    SHAPE ABUTMENT ;
    PORT
      LAYER M4 ;
      RECT 39.288 10.272 39.312 10.296 ;
    END
  END w_mask_in[47]
  PIN w_mask_in[48]
    DIRECTION INPUT ;
    USE SIGNAL ;
    SHAPE ABUTMENT ;
    PORT
      LAYER M4 ;
      RECT 39.288 10.368 39.312 10.392 ;
    END
  END w_mask_in[48]
  PIN w_mask_in[49]
    DIRECTION INPUT ;
    USE SIGNAL ;
    SHAPE ABUTMENT ;
    PORT
      LAYER M4 ;
      RECT 39.288 10.464 39.312 10.488 ;
    END
  END w_mask_in[49]
  PIN w_mask_in[50]
    DIRECTION INPUT ;
    USE SIGNAL ;
    SHAPE ABUTMENT ;
    PORT
      LAYER M4 ;
      RECT 39.288 10.560 39.312 10.584 ;
    END
  END w_mask_in[50]
  PIN w_mask_in[51]
    DIRECTION INPUT ;
    USE SIGNAL ;
    SHAPE ABUTMENT ;
    PORT
      LAYER M4 ;
      RECT 39.288 10.656 39.312 10.680 ;
    END
  END w_mask_in[51]
  PIN w_mask_in[52]
    DIRECTION INPUT ;
    USE SIGNAL ;
    SHAPE ABUTMENT ;
    PORT
      LAYER M4 ;
      RECT 39.288 10.752 39.312 10.776 ;
    END
  END w_mask_in[52]
  PIN w_mask_in[53]
    DIRECTION INPUT ;
    USE SIGNAL ;
    SHAPE ABUTMENT ;
    PORT
      LAYER M4 ;
      RECT 39.288 10.848 39.312 10.872 ;
    END
  END w_mask_in[53]
  PIN w_mask_in[54]
    DIRECTION INPUT ;
    USE SIGNAL ;
    SHAPE ABUTMENT ;
    PORT
      LAYER M4 ;
      RECT 39.288 10.944 39.312 10.968 ;
    END
  END w_mask_in[54]
  PIN w_mask_in[55]
    DIRECTION INPUT ;
    USE SIGNAL ;
    SHAPE ABUTMENT ;
    PORT
      LAYER M4 ;
      RECT 39.288 11.040 39.312 11.064 ;
    END
  END w_mask_in[55]
  PIN w_mask_in[56]
    DIRECTION INPUT ;
    USE SIGNAL ;
    SHAPE ABUTMENT ;
    PORT
      LAYER M4 ;
      RECT 39.288 11.136 39.312 11.160 ;
    END
  END w_mask_in[56]
  PIN w_mask_in[57]
    DIRECTION INPUT ;
    USE SIGNAL ;
    SHAPE ABUTMENT ;
    PORT
      LAYER M4 ;
      RECT 39.288 11.232 39.312 11.256 ;
    END
  END w_mask_in[57]
  PIN w_mask_in[58]
    DIRECTION INPUT ;
    USE SIGNAL ;
    SHAPE ABUTMENT ;
    PORT
      LAYER M4 ;
      RECT 39.288 11.328 39.312 11.352 ;
    END
  END w_mask_in[58]
  PIN w_mask_in[59]
    DIRECTION INPUT ;
    USE SIGNAL ;
    SHAPE ABUTMENT ;
    PORT
      LAYER M4 ;
      RECT 39.288 11.424 39.312 11.448 ;
    END
  END w_mask_in[59]
  PIN w_mask_in[60]
    DIRECTION INPUT ;
    USE SIGNAL ;
    SHAPE ABUTMENT ;
    PORT
      LAYER M4 ;
      RECT 39.288 11.520 39.312 11.544 ;
    END
  END w_mask_in[60]
  PIN w_mask_in[61]
    DIRECTION INPUT ;
    USE SIGNAL ;
    SHAPE ABUTMENT ;
    PORT
      LAYER M4 ;
      RECT 39.288 11.616 39.312 11.640 ;
    END
  END w_mask_in[61]
  PIN w_mask_in[62]
    DIRECTION INPUT ;
    USE SIGNAL ;
    SHAPE ABUTMENT ;
    PORT
      LAYER M4 ;
      RECT 39.288 11.712 39.312 11.736 ;
    END
  END w_mask_in[62]
  PIN w_mask_in[63]
    DIRECTION INPUT ;
    USE SIGNAL ;
    SHAPE ABUTMENT ;
    PORT
      LAYER M4 ;
      RECT 39.288 11.808 39.312 11.832 ;
    END
  END w_mask_in[63]
  PIN w_mask_in[64]
    DIRECTION INPUT ;
    USE SIGNAL ;
    SHAPE ABUTMENT ;
    PORT
      LAYER M4 ;
      RECT 39.288 11.904 39.312 11.928 ;
    END
  END w_mask_in[64]
  PIN w_mask_in[65]
    DIRECTION INPUT ;
    USE SIGNAL ;
    SHAPE ABUTMENT ;
    PORT
      LAYER M4 ;
      RECT 39.288 12.000 39.312 12.024 ;
    END
  END w_mask_in[65]
  PIN w_mask_in[66]
    DIRECTION INPUT ;
    USE SIGNAL ;
    SHAPE ABUTMENT ;
    PORT
      LAYER M4 ;
      RECT 39.288 12.096 39.312 12.120 ;
    END
  END w_mask_in[66]
  PIN w_mask_in[67]
    DIRECTION INPUT ;
    USE SIGNAL ;
    SHAPE ABUTMENT ;
    PORT
      LAYER M4 ;
      RECT 39.288 12.192 39.312 12.216 ;
    END
  END w_mask_in[67]
  PIN w_mask_in[68]
    DIRECTION INPUT ;
    USE SIGNAL ;
    SHAPE ABUTMENT ;
    PORT
      LAYER M4 ;
      RECT 39.288 12.288 39.312 12.312 ;
    END
  END w_mask_in[68]
  PIN w_mask_in[69]
    DIRECTION INPUT ;
    USE SIGNAL ;
    SHAPE ABUTMENT ;
    PORT
      LAYER M4 ;
      RECT 39.288 12.384 39.312 12.408 ;
    END
  END w_mask_in[69]
  PIN w_mask_in[70]
    DIRECTION INPUT ;
    USE SIGNAL ;
    SHAPE ABUTMENT ;
    PORT
      LAYER M4 ;
      RECT 39.288 12.480 39.312 12.504 ;
    END
  END w_mask_in[70]
  PIN w_mask_in[71]
    DIRECTION INPUT ;
    USE SIGNAL ;
    SHAPE ABUTMENT ;
    PORT
      LAYER M4 ;
      RECT 39.288 12.576 39.312 12.600 ;
    END
  END w_mask_in[71]
  PIN w_mask_in[72]
    DIRECTION INPUT ;
    USE SIGNAL ;
    SHAPE ABUTMENT ;
    PORT
      LAYER M4 ;
      RECT 39.288 12.672 39.312 12.696 ;
    END
  END w_mask_in[72]
  PIN w_mask_in[73]
    DIRECTION INPUT ;
    USE SIGNAL ;
    SHAPE ABUTMENT ;
    PORT
      LAYER M4 ;
      RECT 39.288 12.768 39.312 12.792 ;
    END
  END w_mask_in[73]
  PIN w_mask_in[74]
    DIRECTION INPUT ;
    USE SIGNAL ;
    SHAPE ABUTMENT ;
    PORT
      LAYER M4 ;
      RECT 39.288 12.864 39.312 12.888 ;
    END
  END w_mask_in[74]
  PIN w_mask_in[75]
    DIRECTION INPUT ;
    USE SIGNAL ;
    SHAPE ABUTMENT ;
    PORT
      LAYER M4 ;
      RECT 39.288 12.960 39.312 12.984 ;
    END
  END w_mask_in[75]
  PIN w_mask_in[76]
    DIRECTION INPUT ;
    USE SIGNAL ;
    SHAPE ABUTMENT ;
    PORT
      LAYER M4 ;
      RECT 39.288 13.056 39.312 13.080 ;
    END
  END w_mask_in[76]
  PIN w_mask_in[77]
    DIRECTION INPUT ;
    USE SIGNAL ;
    SHAPE ABUTMENT ;
    PORT
      LAYER M4 ;
      RECT 39.288 13.152 39.312 13.176 ;
    END
  END w_mask_in[77]
  PIN w_mask_in[78]
    DIRECTION INPUT ;
    USE SIGNAL ;
    SHAPE ABUTMENT ;
    PORT
      LAYER M4 ;
      RECT 39.288 13.248 39.312 13.272 ;
    END
  END w_mask_in[78]
  PIN w_mask_in[79]
    DIRECTION INPUT ;
    USE SIGNAL ;
    SHAPE ABUTMENT ;
    PORT
      LAYER M4 ;
      RECT 39.288 13.344 39.312 13.368 ;
    END
  END w_mask_in[79]
  PIN w_mask_in[80]
    DIRECTION INPUT ;
    USE SIGNAL ;
    SHAPE ABUTMENT ;
    PORT
      LAYER M4 ;
      RECT 39.288 13.440 39.312 13.464 ;
    END
  END w_mask_in[80]
  PIN w_mask_in[81]
    DIRECTION INPUT ;
    USE SIGNAL ;
    SHAPE ABUTMENT ;
    PORT
      LAYER M4 ;
      RECT 39.288 13.536 39.312 13.560 ;
    END
  END w_mask_in[81]
  PIN w_mask_in[82]
    DIRECTION INPUT ;
    USE SIGNAL ;
    SHAPE ABUTMENT ;
    PORT
      LAYER M4 ;
      RECT 39.288 13.632 39.312 13.656 ;
    END
  END w_mask_in[82]
  PIN w_mask_in[83]
    DIRECTION INPUT ;
    USE SIGNAL ;
    SHAPE ABUTMENT ;
    PORT
      LAYER M4 ;
      RECT 39.288 13.728 39.312 13.752 ;
    END
  END w_mask_in[83]
  PIN w_mask_in[84]
    DIRECTION INPUT ;
    USE SIGNAL ;
    SHAPE ABUTMENT ;
    PORT
      LAYER M4 ;
      RECT 39.288 13.824 39.312 13.848 ;
    END
  END w_mask_in[84]
  PIN w_mask_in[85]
    DIRECTION INPUT ;
    USE SIGNAL ;
    SHAPE ABUTMENT ;
    PORT
      LAYER M4 ;
      RECT 39.288 13.920 39.312 13.944 ;
    END
  END w_mask_in[85]
  PIN w_mask_in[86]
    DIRECTION INPUT ;
    USE SIGNAL ;
    SHAPE ABUTMENT ;
    PORT
      LAYER M4 ;
      RECT 39.288 14.016 39.312 14.040 ;
    END
  END w_mask_in[86]
  PIN w_mask_in[87]
    DIRECTION INPUT ;
    USE SIGNAL ;
    SHAPE ABUTMENT ;
    PORT
      LAYER M4 ;
      RECT 39.288 14.112 39.312 14.136 ;
    END
  END w_mask_in[87]
  PIN w_mask_in[88]
    DIRECTION INPUT ;
    USE SIGNAL ;
    SHAPE ABUTMENT ;
    PORT
      LAYER M4 ;
      RECT 39.288 14.208 39.312 14.232 ;
    END
  END w_mask_in[88]
  PIN w_mask_in[89]
    DIRECTION INPUT ;
    USE SIGNAL ;
    SHAPE ABUTMENT ;
    PORT
      LAYER M4 ;
      RECT 39.288 14.304 39.312 14.328 ;
    END
  END w_mask_in[89]
  PIN w_mask_in[90]
    DIRECTION INPUT ;
    USE SIGNAL ;
    SHAPE ABUTMENT ;
    PORT
      LAYER M4 ;
      RECT 39.288 14.400 39.312 14.424 ;
    END
  END w_mask_in[90]
  PIN w_mask_in[91]
    DIRECTION INPUT ;
    USE SIGNAL ;
    SHAPE ABUTMENT ;
    PORT
      LAYER M4 ;
      RECT 39.288 14.496 39.312 14.520 ;
    END
  END w_mask_in[91]
  PIN w_mask_in[92]
    DIRECTION INPUT ;
    USE SIGNAL ;
    SHAPE ABUTMENT ;
    PORT
      LAYER M4 ;
      RECT 39.288 14.592 39.312 14.616 ;
    END
  END w_mask_in[92]
  PIN w_mask_in[93]
    DIRECTION INPUT ;
    USE SIGNAL ;
    SHAPE ABUTMENT ;
    PORT
      LAYER M4 ;
      RECT 39.288 14.688 39.312 14.712 ;
    END
  END w_mask_in[93]
  PIN w_mask_in[94]
    DIRECTION INPUT ;
    USE SIGNAL ;
    SHAPE ABUTMENT ;
    PORT
      LAYER M4 ;
      RECT 39.288 14.784 39.312 14.808 ;
    END
  END w_mask_in[94]
  PIN w_mask_in[95]
    DIRECTION INPUT ;
    USE SIGNAL ;
    SHAPE ABUTMENT ;
    PORT
      LAYER M4 ;
      RECT 39.288 14.880 39.312 14.904 ;
    END
  END w_mask_in[95]
  PIN w_mask_in[96]
    DIRECTION INPUT ;
    USE SIGNAL ;
    SHAPE ABUTMENT ;
    PORT
      LAYER M4 ;
      RECT 39.288 14.976 39.312 15.000 ;
    END
  END w_mask_in[96]
  PIN VDD
    DIRECTION INOUT ;
    USE POWER ;
    PORT
      LAYER M4 ;
      RECT 0.300 0.384 39.012 0.480 ;
      RECT 0.300 1.152 39.012 1.248 ;
      RECT 0.300 1.920 39.012 2.016 ;
      RECT 0.300 2.688 39.012 2.784 ;
      RECT 0.300 3.456 39.012 3.552 ;
      RECT 0.300 4.224 39.012 4.320 ;
      RECT 0.300 4.992 39.012 5.088 ;
      RECT 0.300 5.760 39.012 5.856 ;
      RECT 0.300 6.528 39.012 6.624 ;
      RECT 0.300 7.296 39.012 7.392 ;
      RECT 0.300 8.064 39.012 8.160 ;
      RECT 0.300 8.832 39.012 8.928 ;
      RECT 0.300 9.600 39.012 9.696 ;
      RECT 0.300 10.368 39.012 10.464 ;
      RECT 0.300 11.136 39.012 11.232 ;
      RECT 0.300 11.904 39.012 12.000 ;
      RECT 0.300 12.672 39.012 12.768 ;
      RECT 0.300 13.440 39.012 13.536 ;
      RECT 0.300 14.208 39.012 14.304 ;
      RECT 0.300 14.976 39.012 15.072 ;
      RECT 0.300 15.744 39.012 15.840 ;
    END
  END VDD
  PIN VSS
    DIRECTION INOUT ;
    USE GROUND ;
    PORT
      LAYER M4 ;
      RECT 0.300 0.768 39.012 0.864 ;
      RECT 0.300 1.536 39.012 1.632 ;
      RECT 0.300 2.304 39.012 2.400 ;
      RECT 0.300 3.072 39.012 3.168 ;
      RECT 0.300 3.840 39.012 3.936 ;
      RECT 0.300 4.608 39.012 4.704 ;
      RECT 0.300 5.376 39.012 5.472 ;
      RECT 0.300 6.144 39.012 6.240 ;
      RECT 0.300 6.912 39.012 7.008 ;
      RECT 0.300 7.680 39.012 7.776 ;
      RECT 0.300 8.448 39.012 8.544 ;
      RECT 0.300 9.216 39.012 9.312 ;
      RECT 0.300 9.984 39.012 10.080 ;
      RECT 0.300 10.752 39.012 10.848 ;
      RECT 0.300 11.520 39.012 11.616 ;
      RECT 0.300 12.288 39.012 12.384 ;
      RECT 0.300 13.056 39.012 13.152 ;
      RECT 0.300 13.824 39.012 13.920 ;
      RECT 0.300 14.592 39.012 14.688 ;
      RECT 0.300 15.360 39.012 15.456 ;
    END
  END VSS
  OBS
    LAYER M1 ;
    RECT 0 0 39.312 16.200 ;
    LAYER M2 ;
    RECT 0 0 39.312 16.200 ;
    LAYER M3 ;
    RECT 0 0 39.312 16.200 ;
    LAYER M4 ;
    RECT 0.072 0 39.240 16.200 ;
  END
END ot_sram_1r1w2c_4x97_m1

END LIBRARY
